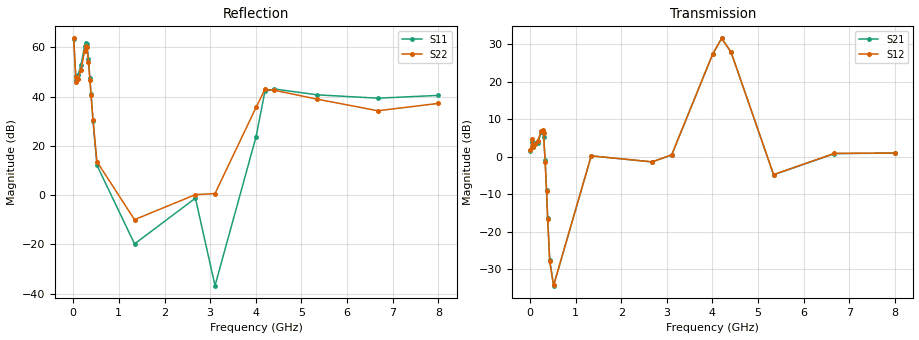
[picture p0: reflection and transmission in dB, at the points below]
!Agilent Technologies,N5230A,US43500312,A.07.50.67
!Agilent N5230A: A.07.50.67
!Date: Tuesday, June 09, 2015 15:40:57
!Correction: S11(Full 2 Port(1,2))
!S21(Full 2 Port(1,2))
!S12(Full 2 Port(1,2))
!S22(Full 2 Port(1,2))
!S2P File: Measurements: S11, S21, S12, S22:
# Hz S  MA  R 50
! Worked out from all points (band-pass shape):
!   1601 points, 10 MHz to 8 GHz, reference 50 ohm
!   highest |S21| = 31.57 dB at 4.2 GHz (marker M1); lowest = -34.3 dB at 519.4 MHz (marker M2)
!   |S21| within 3 dB of the highest: 4.037 GHz to 4.379 GHz (341.1 MHz wide, 8.11 % of centre)
!   lowest |S11| = -36.7 dB at 3.106 GHz (marker M3), VSWR 1.03, Z = 48.9 - j0.872 ohm
!   |S11| at or under -10 dB: 994.2 MHz to 1.882 GHz (887.3 MHz wide, 61.7 % of centre); 2.122 GHz to 2.336 GHz (214.4 MHz wide, 9.62 % of centre); 3.037 GHz to 3.162 GHz (125.6 MHz wide, 4.05 % of centre)
!   |S22| runs from -16.1 to 63.6 dB; largest |S21 - S12| = 0.6
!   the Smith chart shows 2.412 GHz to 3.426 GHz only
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1e7  1488 171.1  1.194 21.1  1.231 -7.4  1520 -19.4
5.494375e7  259.2 327.7  1.597 9.0  1.717 9.2  244.8 94.0
6.493125e7  219 339.5  1.375 5.6  1.343 6.3  199.7 98.3
1.048812e8  270.7 377.5  1.514 5.4  1.481 7.5  229 116.5
1.698e8  439.7 415.8  1.539 13.1  1.629 10.3  348.5 134.7
2.497e8  1050 414.8  2.123 15.4  2.2 10.0  858.2 127.9
2.796625e8  1253 429.0  2.195 32.0  2.311 35.4  1051 142.6
2.996375e8  1170 438.3  1.839 42.9  2.068 43.3  1001 153.0
3.345938e8  578 472.9  0.897 87.0  0.8553 84.1  513.8 190.6
3.645562e8  237.8 483.6  0.3607 100.4  0.352 94.0  220.3 206.1
3.89525e8  113.7 491.5  0.1533 108.8  0.1479 99.3  109.1 218.8
4.344688e8  31.79 500.7  0.04187 107.7  0.04046 101.8  32.94 240.4
5.193625e8  4.055 527.4  0.01922 125.7  0.0194 126.4  4.791 300.6
1.343331e9  0.1025 811.8  1.033 176.0  1.033 176.0  0.3186 789.9
2.676662e9  0.8707 702.3  0.8565 177.7  0.8593 177.8  1.026 1242.3
3.106125e9  0.01457 577.8  1.063 199.9  1.065 200.0  1.08 1350.9
4.005e9  15.35 460.8  23.5 240.5  23.53 240.7  60.48 1534.2
4.199756e9  128.4 362.9  37.9 157.3  38 157.5  140.3 1490.9
4.4045e9  143 304.0  25.07 82.7  25.15 82.7  134.7 1449.4
5.338331e9  108.7 297.6  0.5782 8.9  0.5812 9.2  89.02 1419.6
6.671662e9  92.91 314.6  1.106 28.1  1.115 28.5  51.65 1363.4
8e9  105.8 326.8  1.126 17.7  1.126 18.2  72.83 1321.8
